VERSION 5.7 ;
  NAMESCASESENSITIVE ON ;
  NOWIREEXTENSIONATPIN ON ;
  DIVIDERCHAR "/" ;
  BUSBITCHARS "[]" ;
UNITS
  DATABASE MICRONS 200 ;
END UNITS

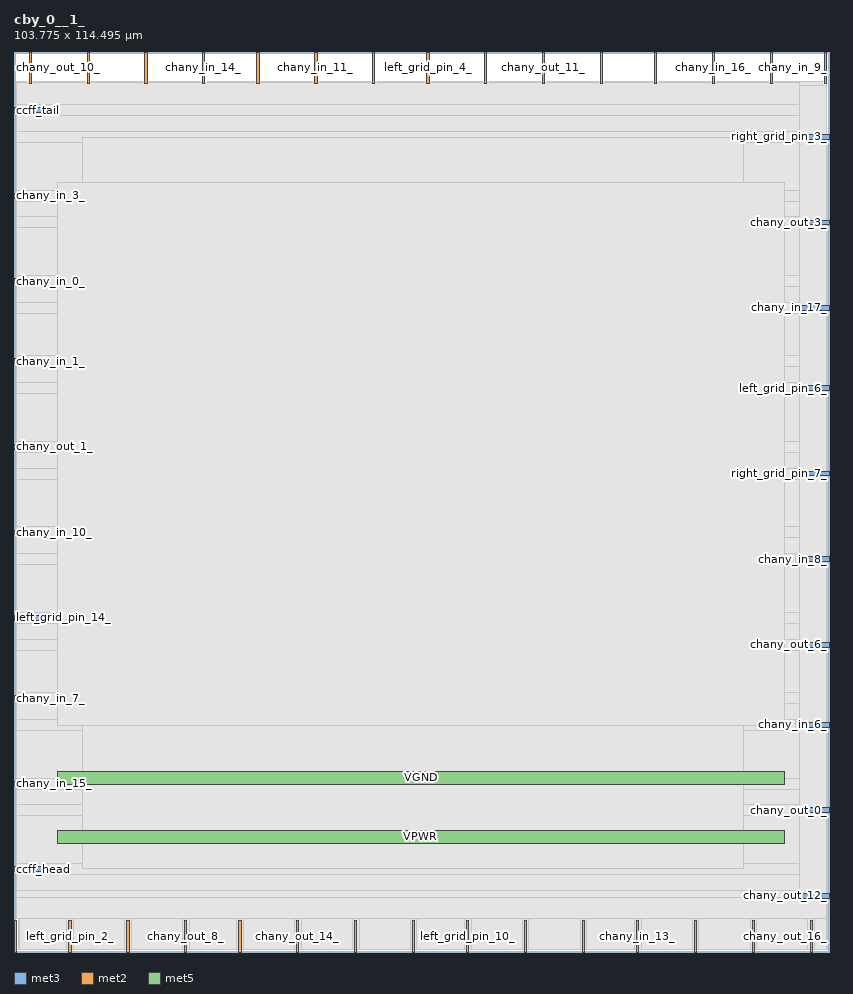
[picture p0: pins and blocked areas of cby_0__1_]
MACRO cby_0__1_
  CLASS BLOCK ;
  FOREIGN cby_0__1_ ;
  ORIGIN 0.000 0.000 ;
  SIZE 103.775 BY 114.495 ;
  PIN ccff_head
    DIRECTION INPUT ;
    PORT
      LAYER met3 ;
        RECT 0.000 10.240 4.000 10.840 ;
    END
  END ccff_head
  PIN ccff_tail
    DIRECTION OUTPUT TRISTATE ;
    PORT
      LAYER met3 ;
        RECT 0.000 106.800 4.000 107.400 ;
    END
  END ccff_tail
  PIN chany_in_0_
    DIRECTION INPUT ;
    PORT
      LAYER met3 ;
        RECT 0.000 85.040 4.000 85.640 ;
    END
  END chany_in_0_
  PIN chany_in_10_
    DIRECTION INPUT ;
    PORT
      LAYER met3 ;
        RECT 0.000 53.080 4.000 53.680 ;
    END
  END chany_in_10_
  PIN chany_in_11_
    DIRECTION INPUT ;
    PORT
      LAYER met2 ;
        RECT 38.270 110.495 38.550 114.495 ;
    END
  END chany_in_11_
  PIN chany_in_12_
    DIRECTION INPUT ;
    PORT
      LAYER met2 ;
        RECT 64.950 0.000 65.230 4.000 ;
    END
  END chany_in_12_
  PIN chany_in_13_
    DIRECTION INPUT ;
    PORT
      LAYER met2 ;
        RECT 79.210 0.000 79.490 4.000 ;
    END
  END chany_in_13_
  PIN chany_in_14_
    DIRECTION INPUT ;
    PORT
      LAYER met2 ;
        RECT 24.010 110.495 24.290 114.495 ;
    END
  END chany_in_14_
  PIN chany_in_15_
    DIRECTION INPUT ;
    PORT
      LAYER met3 ;
        RECT 0.000 21.120 4.000 21.720 ;
    END
  END chany_in_15_
  PIN chany_in_16_
    DIRECTION INPUT ;
    PORT
      LAYER met2 ;
        RECT 88.870 110.495 89.150 114.495 ;
    END
  END chany_in_16_
  PIN chany_in_17_
    DIRECTION INPUT ;
    PORT
      LAYER met3 ;
        RECT 99.775 81.640 103.775 82.240 ;
    END
  END chany_in_17_
  PIN chany_in_1_
    DIRECTION INPUT ;
    PORT
      LAYER met3 ;
        RECT 0.000 74.840 4.000 75.440 ;
    END
  END chany_in_1_
  PIN chany_in_2_
    DIRECTION INPUT ;
    PORT
      LAYER met2 ;
        RECT 86.570 0.000 86.850 4.000 ;
    END
  END chany_in_2_
  PIN chany_in_3_
    DIRECTION INPUT ;
    PORT
      LAYER met3 ;
        RECT 0.000 95.920 4.000 96.520 ;
    END
  END chany_in_3_
  PIN chany_in_4_
    DIRECTION INPUT ;
    PORT
      LAYER met2 ;
        RECT 45.630 110.495 45.910 114.495 ;
    END
  END chany_in_4_
  PIN chany_in_5_
    DIRECTION INPUT ;
    PORT
      LAYER met2 ;
        RECT 14.350 0.000 14.630 4.000 ;
    END
  END chany_in_5_
  PIN chany_in_6_
    DIRECTION INPUT ;
    PORT
      LAYER met3 ;
        RECT 99.775 28.600 103.775 29.200 ;
    END
  END chany_in_6_
  PIN chany_in_7_
    DIRECTION INPUT ;
    PORT
      LAYER met3 ;
        RECT 0.000 32.000 4.000 32.600 ;
    END
  END chany_in_7_
  PIN chany_in_8_
    DIRECTION INPUT ;
    PORT
      LAYER met3 ;
        RECT 99.775 49.680 103.775 50.280 ;
    END
  END chany_in_8_
  PIN chany_in_9_
    DIRECTION INPUT ;
    PORT
      LAYER met2 ;
        RECT 103.130 110.495 103.410 114.495 ;
    END
  END chany_in_9_
  PIN chany_out_0_
    DIRECTION OUTPUT TRISTATE ;
    PORT
      LAYER met3 ;
        RECT 99.775 17.720 103.775 18.320 ;
    END
  END chany_out_0_
  PIN chany_out_10_
    DIRECTION OUTPUT TRISTATE ;
    PORT
      LAYER met2 ;
        RECT 1.930 110.495 2.210 114.495 ;
    END
  END chany_out_10_
  PIN chany_out_11_
    DIRECTION OUTPUT TRISTATE ;
    PORT
      LAYER met2 ;
        RECT 67.250 110.495 67.530 114.495 ;
    END
  END chany_out_11_
  PIN chany_out_12_
    DIRECTION OUTPUT TRISTATE ;
    PORT
      LAYER met3 ;
        RECT 99.775 6.840 103.775 7.440 ;
    END
  END chany_out_12_
  PIN chany_out_13_
    DIRECTION OUTPUT TRISTATE ;
    PORT
      LAYER met2 ;
        RECT 30.910 110.495 31.190 114.495 ;
    END
  END chany_out_13_
  PIN chany_out_14_
    DIRECTION OUTPUT TRISTATE ;
    PORT
      LAYER met2 ;
        RECT 35.970 0.000 36.250 4.000 ;
    END
  END chany_out_14_
  PIN chany_out_15_
    DIRECTION OUTPUT TRISTATE ;
    PORT
      LAYER met2 ;
        RECT 16.650 110.495 16.930 114.495 ;
    END
  END chany_out_15_
  PIN chany_out_16_
    DIRECTION OUTPUT TRISTATE ;
    PORT
      LAYER met2 ;
        RECT 101.290 0.000 101.570 4.000 ;
    END
  END chany_out_16_
  PIN chany_out_17_
    DIRECTION OUTPUT TRISTATE ;
    PORT
      LAYER met2 ;
        RECT 81.510 110.495 81.790 114.495 ;
    END
  END chany_out_17_
  PIN chany_out_1_
    DIRECTION OUTPUT TRISTATE ;
    PORT
      LAYER met3 ;
        RECT 0.000 63.960 4.000 64.560 ;
    END
  END chany_out_1_
  PIN chany_out_2_
    DIRECTION OUTPUT TRISTATE ;
    PORT
      LAYER met2 ;
        RECT 50.690 0.000 50.970 4.000 ;
    END
  END chany_out_2_
  PIN chany_out_3_
    DIRECTION OUTPUT TRISTATE ;
    PORT
      LAYER met3 ;
        RECT 99.775 92.520 103.775 93.120 ;
    END
  END chany_out_3_
  PIN chany_out_4_
    DIRECTION OUTPUT TRISTATE ;
    PORT
      LAYER met2 ;
        RECT 74.610 110.495 74.890 114.495 ;
    END
  END chany_out_4_
  PIN chany_out_5_
    DIRECTION OUTPUT TRISTATE ;
    PORT
      LAYER met2 ;
        RECT 96.230 110.495 96.510 114.495 ;
    END
  END chany_out_5_
  PIN chany_out_6_
    DIRECTION OUTPUT TRISTATE ;
    PORT
      LAYER met3 ;
        RECT 99.775 38.800 103.775 39.400 ;
    END
  END chany_out_6_
  PIN chany_out_7_
    DIRECTION OUTPUT TRISTATE ;
    PORT
      LAYER met2 ;
        RECT 28.610 0.000 28.890 4.000 ;
    END
  END chany_out_7_
  PIN chany_out_8_
    DIRECTION OUTPUT TRISTATE ;
    PORT
      LAYER met2 ;
        RECT 21.710 0.000 21.990 4.000 ;
    END
  END chany_out_8_
  PIN chany_out_9_
    DIRECTION OUTPUT TRISTATE ;
    PORT
      LAYER met2 ;
        RECT 93.930 0.000 94.210 4.000 ;
    END
  END chany_out_9_
  PIN left_grid_pin_0_
    DIRECTION OUTPUT TRISTATE ;
    PORT
      LAYER met2 ;
        RECT 72.310 0.000 72.590 4.000 ;
    END
  END left_grid_pin_0_
  PIN left_grid_pin_10_
    DIRECTION OUTPUT TRISTATE ;
    PORT
      LAYER met2 ;
        RECT 57.590 0.000 57.870 4.000 ;
    END
  END left_grid_pin_10_
  PIN left_grid_pin_12_
    DIRECTION OUTPUT TRISTATE ;
    PORT
      LAYER met2 ;
        RECT 43.330 0.000 43.610 4.000 ;
    END
  END left_grid_pin_12_
  PIN left_grid_pin_14_
    DIRECTION OUTPUT TRISTATE ;
    PORT
      LAYER met3 ;
        RECT 0.000 42.200 4.000 42.800 ;
    END
  END left_grid_pin_14_
  PIN left_grid_pin_2_
    DIRECTION OUTPUT TRISTATE ;
    PORT
      LAYER met2 ;
        RECT 6.990 0.000 7.270 4.000 ;
    END
  END left_grid_pin_2_
  PIN left_grid_pin_4_
    DIRECTION OUTPUT TRISTATE ;
    PORT
      LAYER met2 ;
        RECT 52.530 110.495 52.810 114.495 ;
    END
  END left_grid_pin_4_
  PIN left_grid_pin_6_
    DIRECTION OUTPUT TRISTATE ;
    PORT
      LAYER met3 ;
        RECT 99.775 71.440 103.775 72.040 ;
    END
  END left_grid_pin_6_
  PIN left_grid_pin_8_
    DIRECTION OUTPUT TRISTATE ;
    PORT
      LAYER met2 ;
        RECT 0.090 0.000 0.370 4.000 ;
    END
  END left_grid_pin_8_
  PIN pReset
    DIRECTION INPUT ;
    PORT
      LAYER met2 ;
        RECT 9.290 110.495 9.570 114.495 ;
    END
  END pReset
  PIN prog_clk
    DIRECTION INPUT ;
    PORT
      LAYER met2 ;
        RECT 59.890 110.495 60.170 114.495 ;
    END
  END prog_clk
  PIN right_grid_pin_3_
    DIRECTION OUTPUT TRISTATE ;
    PORT
      LAYER met3 ;
        RECT 99.775 103.400 103.775 104.000 ;
    END
  END right_grid_pin_3_
  PIN right_grid_pin_7_
    DIRECTION OUTPUT TRISTATE ;
    PORT
      LAYER met3 ;
        RECT 99.775 60.560 103.775 61.160 ;
    END
  END right_grid_pin_7_
  PIN VPWR
    DIRECTION INPUT ;
    USE POWER ;
    PORT
      LAYER met5 ;
        RECT 5.520 13.840 97.980 15.440 ;
    END
  END VPWR
  PIN VGND
    DIRECTION INPUT ;
    USE GROUND ;
    PORT
      LAYER met5 ;
        RECT 5.520 21.340 97.980 22.940 ;
    END
  END VGND
  OBS
      LAYER li1 ;
        RECT 5.520 10.795 97.980 103.445 ;
      LAYER met1 ;
        RECT 0.530 0.380 103.430 103.600 ;
      LAYER met2 ;
        RECT 0.370 110.215 1.650 110.685 ;
        RECT 2.490 110.215 9.010 110.685 ;
        RECT 9.850 110.215 16.370 110.685 ;
        RECT 17.210 110.215 23.730 110.685 ;
        RECT 24.570 110.215 30.630 110.685 ;
        RECT 31.470 110.215 37.990 110.685 ;
        RECT 38.830 110.215 45.350 110.685 ;
        RECT 46.190 110.215 52.250 110.685 ;
        RECT 53.090 110.215 59.610 110.685 ;
        RECT 60.450 110.215 66.970 110.685 ;
        RECT 67.810 110.215 74.330 110.685 ;
        RECT 75.170 110.215 81.230 110.685 ;
        RECT 82.070 110.215 88.590 110.685 ;
        RECT 89.430 110.215 95.950 110.685 ;
        RECT 96.790 110.215 102.850 110.685 ;
        RECT 0.370 4.280 103.400 110.215 ;
        RECT 0.650 0.270 6.710 4.280 ;
        RECT 7.550 0.270 14.070 4.280 ;
        RECT 14.910 0.270 21.430 4.280 ;
        RECT 22.270 0.270 28.330 4.280 ;
        RECT 29.170 0.270 35.690 4.280 ;
        RECT 36.530 0.270 43.050 4.280 ;
        RECT 43.890 0.270 50.410 4.280 ;
        RECT 51.250 0.270 57.310 4.280 ;
        RECT 58.150 0.270 64.670 4.280 ;
        RECT 65.510 0.270 72.030 4.280 ;
        RECT 72.870 0.270 78.930 4.280 ;
        RECT 79.770 0.270 86.290 4.280 ;
        RECT 87.130 0.270 93.650 4.280 ;
        RECT 94.490 0.270 101.010 4.280 ;
        RECT 101.850 0.270 103.400 4.280 ;
      LAYER met3 ;
        RECT 0.310 107.800 99.970 110.665 ;
        RECT 4.400 106.400 99.970 107.800 ;
        RECT 0.310 104.400 99.970 106.400 ;
        RECT 0.310 103.000 99.375 104.400 ;
        RECT 0.310 96.920 99.970 103.000 ;
        RECT 4.400 95.520 99.970 96.920 ;
        RECT 0.310 93.520 99.970 95.520 ;
        RECT 0.310 92.120 99.375 93.520 ;
        RECT 0.310 86.040 99.970 92.120 ;
        RECT 4.400 84.640 99.970 86.040 ;
        RECT 0.310 82.640 99.970 84.640 ;
        RECT 0.310 81.240 99.375 82.640 ;
        RECT 0.310 75.840 99.970 81.240 ;
        RECT 4.400 74.440 99.970 75.840 ;
        RECT 0.310 72.440 99.970 74.440 ;
        RECT 0.310 71.040 99.375 72.440 ;
        RECT 0.310 64.960 99.970 71.040 ;
        RECT 4.400 63.560 99.970 64.960 ;
        RECT 0.310 61.560 99.970 63.560 ;
        RECT 0.310 60.160 99.375 61.560 ;
        RECT 0.310 54.080 99.970 60.160 ;
        RECT 4.400 52.680 99.970 54.080 ;
        RECT 0.310 50.680 99.970 52.680 ;
        RECT 0.310 49.280 99.375 50.680 ;
        RECT 0.310 43.200 99.970 49.280 ;
        RECT 4.400 41.800 99.970 43.200 ;
        RECT 0.310 39.800 99.970 41.800 ;
        RECT 0.310 38.400 99.375 39.800 ;
        RECT 0.310 33.000 99.970 38.400 ;
        RECT 4.400 31.600 99.970 33.000 ;
        RECT 0.310 29.600 99.970 31.600 ;
        RECT 0.310 28.200 99.375 29.600 ;
        RECT 0.310 22.120 99.970 28.200 ;
        RECT 4.400 20.720 99.970 22.120 ;
        RECT 0.310 18.720 99.970 20.720 ;
        RECT 0.310 17.320 99.375 18.720 ;
        RECT 0.310 11.240 99.970 17.320 ;
        RECT 4.400 9.840 99.970 11.240 ;
        RECT 0.310 7.840 99.970 9.840 ;
        RECT 0.310 6.975 99.375 7.840 ;
      LAYER met4 ;
        RECT 8.720 10.640 92.820 103.600 ;
      LAYER met5 ;
        RECT 5.520 28.840 97.980 97.940 ;
  END
END cby_0__1_
END LIBRARY

